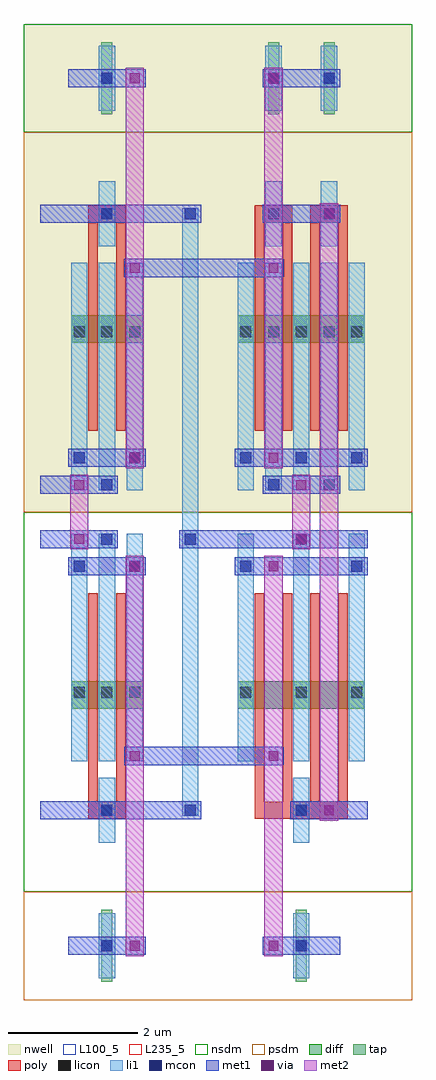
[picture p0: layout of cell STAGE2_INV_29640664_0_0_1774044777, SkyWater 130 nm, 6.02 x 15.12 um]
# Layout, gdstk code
from math import pi, radians
import gdstk
lib = gdstk.Library(unit=1e-6, precision=1e-09)
def R(c, l, rs):  # rectangles x0, y0, x1, y1
    for r in rs: c.add(gdstk.rectangle(r[:2], r[2:], *l))
def A(c, l, x, y, w, h, nx, ny, dx, dy):  # array of equal rectangles
    R(c, l, [(x+i*dx, y+j*dy, x+i*dx+w, y+j*dy+h) for i in range(nx) for j in range(ny)])
def P(c, l, *ps):  # polygons
    for p in ps: c.add(gdstk.Polygon(p, *l))
nwell = (64, 20)
diff = (65, 20)
tap = (65, 44)
poly = (66, 20)
licon = (66, 44)
li1 = (67, 20)
mcon = (67, 44)
met1 = (68, 20)
via = (68, 44)
met2 = (69, 20)
nsdm = (93, 44)
psdm = (94, 20)
L100_5 = (100, 5)
L235_5 = (235, 5)

nmos_s_30545730_x1_y1_17 = lib.new_cell('NMOS_S_30545730_X1_Y1_1774044755_1774044777')
R(nmos_s_30545730_x1_y1_17, diff, [(0.735,2.625,2.705,3.045)])
R(nmos_s_30545730_x1_y1_17, tap, [(1.635,6.16,1.805,7.28)])
A(nmos_s_30545730_x1_y1_17, poly, 1, 1.26, 0.15, 3.36, 4, 1, 0.43, 0)
R(nmos_s_30545730_x1_y1_17, poly, [(1,4.485,2.44,4.755)])
A(nmos_s_30545730_x1_y1_17, licon, 0.775, 2.705, 0.17, 0.17, 3, 1, 0.86, 0)
R(nmos_s_30545730_x1_y1_17, licon, [(1.635,4.535,1.805,4.705), (1.635,6.635,1.805,6.805)])
A(nmos_s_30545730_x1_y1_17, li1, 0.735, 0.335, 0.25, 3.53, 3, 1, 0.86, 0)
R(nmos_s_30545730_x1_y1_17, li1, [(1.595,4.115,1.845,5.125), (1.595,6.215,1.845,7.225)])
R(nmos_s_30545730_x1_y1_17, mcon, [(1.635,0.335,1.805,0.505), (0.775,0.755,0.945,0.925), (2.495,0.755,2.665,0.925), (1.635,4.535,1.805,4.705), (1.635,6.635,1.805,6.805)])
R(nmos_s_30545730_x1_y1_17, met1, [(0.69,0.28,1.89,0.56), (0.69,0.7,2.75,0.98), (0.69,4.48,1.89,4.76), (1.12,6.58,2.32,6.86)])
R(nmos_s_30545730_x1_y1_17, via, [(2.075,0.765,2.225,0.915), (2.075,6.645,2.225,6.795)])
R(nmos_s_30545730_x1_y1_17, met2, [(2.01,0.68,2.29,6.88)])
R(nmos_s_30545730_x1_y1_17, nsdm, [(0,0,3.44,5.88)])
R(nmos_s_30545730_x1_y1_17, psdm, [(0,5.88,3.44,7.56)])
R(nmos_s_30545730_x1_y1_17, L100_5, [(0,0,3.44,7.56)])

nmos_s_96839798_x1_y1_17 = lib.new_cell('NMOS_S_96839798_X1_Y1_1774044756_1774044777')
R(nmos_s_96839798_x1_y1_17, diff, [(0.735,2.625,1.845,3.045)])
R(nmos_s_96839798_x1_y1_17, tap, [(1.205,6.16,1.375,7.28)])
R(nmos_s_96839798_x1_y1_17, poly, [(1,1.26,1.15,4.62), (1.43,1.26,1.58,4.62), (1,4.485,1.58,4.755)])
A(nmos_s_96839798_x1_y1_17, licon, 0.775, 2.705, 0.17, 0.17, 3, 1, 0.43, 0)
R(nmos_s_96839798_x1_y1_17, licon, [(1.205,4.535,1.375,4.705), (1.205,6.635,1.375,6.805)])
A(nmos_s_96839798_x1_y1_17, li1, 0.735, 0.335, 0.25, 3.53, 3, 1, 0.43, 0)
R(nmos_s_96839798_x1_y1_17, li1, [(1.165,4.115,1.415,5.125), (1.165,6.215,1.415,7.225)])
R(nmos_s_96839798_x1_y1_17, mcon, [(1.205,0.335,1.375,0.505), (0.775,0.755,0.945,0.925), (1.635,0.755,1.805,0.925), (1.205,4.535,1.375,4.705), (1.205,6.635,1.375,6.805)])
R(nmos_s_96839798_x1_y1_17, met1, [(0.26,0.28,1.46,0.56), (0.69,0.7,1.89,0.98), (0.26,4.48,1.46,4.76), (0.69,6.58,1.89,6.86)])
R(nmos_s_96839798_x1_y1_17, via, [(1.645,0.765,1.795,0.915), (1.645,6.645,1.795,6.795)])
R(nmos_s_96839798_x1_y1_17, met2, [(1.58,0.68,1.86,6.88)])
R(nmos_s_96839798_x1_y1_17, nsdm, [(0,0,2.58,5.88)])
R(nmos_s_96839798_x1_y1_17, psdm, [(0,5.88,2.58,7.56)])
R(nmos_s_96839798_x1_y1_17, L100_5, [(0,0,2.58,7.56)])

pmos_s_9692504_x2_y1_177 = lib.new_cell('PMOS_S_9692504_X2_Y1_1774044758_1774044777')
R(pmos_s_9692504_x2_y1_177, nwell, [(0,0,3.44,7.56)])
R(pmos_s_9692504_x2_y1_177, diff, [(0.735,2.625,2.705,3.045)])
R(pmos_s_9692504_x2_y1_177, tap, [(1.205,6.16,1.375,7.28), (2.065,6.16,2.235,7.28)])
A(pmos_s_9692504_x2_y1_177, poly, 1, 1.26, 0.15, 3.36, 4, 1, 0.43, 0)
R(pmos_s_9692504_x2_y1_177, poly, [(1,4.485,1.58,4.755), (1.86,4.485,2.44,4.755)])
A(pmos_s_9692504_x2_y1_177, licon, 0.775, 2.705, 0.17, 0.17, 3, 1, 0.43, 0)
A(pmos_s_9692504_x2_y1_177, licon, 1.635, 2.705, 0.17, 0.17, 3, 1, 0.43, 0)
R(pmos_s_9692504_x2_y1_177, licon, [(1.205,4.535,1.375,4.705), (2.065,4.535,2.235,4.705), (1.205,6.635,1.375,6.805), (2.065,6.635,2.235,6.805)])
A(pmos_s_9692504_x2_y1_177, li1, 0.735, 0.335, 0.25, 3.53, 5, 1, 0.43, 0)
R(pmos_s_9692504_x2_y1_177, li1, [(1.165,4.115,1.415,5.125), (2.025,4.115,2.275,5.125), (1.165,6.215,1.415,7.225), (2.025,6.215,2.275,7.225)])
A(pmos_s_9692504_x2_y1_177, mcon, 0.775, 0.755, 0.17, 0.17, 3, 1, 0.86, 0)
R(pmos_s_9692504_x2_y1_177, mcon, [(1.205,0.335,1.375,0.505), (2.065,0.335,2.235,0.505), (1.205,4.535,1.375,4.705), (2.065,4.535,2.235,4.705), (1.205,6.635,1.375,6.805), (2.065,6.635,2.235,6.805)])
R(pmos_s_9692504_x2_y1_177, met1, [(1.12,0.28,2.32,0.56), (0.69,0.7,2.75,0.98), (1.12,4.48,2.32,4.76), (1.12,6.58,2.32,6.86)])
R(pmos_s_9692504_x2_y1_177, via, [(2.075,0.765,2.225,0.915), (2.075,6.645,2.225,6.795)])
R(pmos_s_9692504_x2_y1_177, met2, [(2.01,0.68,2.29,6.88)])
R(pmos_s_9692504_x2_y1_177, nsdm, [(0,5.88,3.44,7.56)])
R(pmos_s_9692504_x2_y1_177, psdm, [(0,0,3.44,5.88)])
R(pmos_s_9692504_x2_y1_177, L100_5, [(0,0,3.44,7.56)])

pmos_s_48783884_x1_y1_17 = lib.new_cell('PMOS_S_48783884_X1_Y1_1774044757_1774044777')
R(pmos_s_48783884_x1_y1_17, nwell, [(0,0,2.58,7.56)])
R(pmos_s_48783884_x1_y1_17, diff, [(0.735,2.625,1.845,3.045)])
R(pmos_s_48783884_x1_y1_17, tap, [(1.205,6.16,1.375,7.28)])
R(pmos_s_48783884_x1_y1_17, poly, [(1,1.26,1.15,4.62), (1.43,1.26,1.58,4.62), (1,4.485,1.58,4.755)])
A(pmos_s_48783884_x1_y1_17, licon, 0.775, 2.705, 0.17, 0.17, 3, 1, 0.43, 0)
R(pmos_s_48783884_x1_y1_17, licon, [(1.205,4.535,1.375,4.705), (1.205,6.635,1.375,6.805)])
A(pmos_s_48783884_x1_y1_17, li1, 0.735, 0.335, 0.25, 3.53, 3, 1, 0.43, 0)
R(pmos_s_48783884_x1_y1_17, li1, [(1.165,4.115,1.415,5.125), (1.165,6.215,1.415,7.225)])
R(pmos_s_48783884_x1_y1_17, mcon, [(1.205,0.335,1.375,0.505), (0.775,0.755,0.945,0.925), (1.635,0.755,1.805,0.925), (1.205,4.535,1.375,4.705), (1.205,6.635,1.375,6.805)])
R(pmos_s_48783884_x1_y1_17, met1, [(0.26,0.28,1.46,0.56), (0.69,0.7,1.89,0.98), (0.26,4.48,1.46,4.76), (0.69,6.58,1.89,6.86)])
R(pmos_s_48783884_x1_y1_17, via, [(1.645,0.765,1.795,0.915), (1.645,6.645,1.795,6.795)])
R(pmos_s_48783884_x1_y1_17, met2, [(1.58,0.68,1.86,6.88)])
R(pmos_s_48783884_x1_y1_17, nsdm, [(0,5.88,2.58,7.56)])
R(pmos_s_48783884_x1_y1_17, psdm, [(0,0,2.58,5.88)])
R(pmos_s_48783884_x1_y1_17, L100_5, [(0,0,2.58,7.56)])

stage2_inv_29640664_0_0_ = lib.new_cell('STAGE2_INV_29640664_0_0_1774044777')
R(stage2_inv_29640664_0_0_, li1, [(2.455,2.855,2.705,3.025), (2.455,2.855,2.705,3.025), (2.455,2.855,2.705,3.025), (2.455,2.855,2.705,3.025), (2.455,2.855,2.705,3.025), (2.455,2.855,2.705,3.025), (2.455,2.94,2.705,7.14), (2.455,7.055,2.705,7.225), (2.455,7.055,2.705,7.225), (2.455,7.055,2.705,7.225), (2.455,7.055,2.705,7.225), (2.455,7.055,2.705,7.225), (2.455,7.055,2.705,7.225), (2.455,7.14,2.705,12.18), (2.455,12.095,2.705,12.265), (2.455,12.095,2.705,12.265)])
R(stage2_inv_29640664_0_0_, mcon, [(2.495,2.855,2.665,3.025), (2.495,2.855,2.665,3.025), (2.495,2.855,2.665,3.025), (2.495,2.855,2.665,3.025), (2.495,2.855,2.665,3.025), (2.495,2.855,2.665,3.025), (2.495,7.055,2.665,7.225), (2.495,7.055,2.665,7.225), (2.495,7.055,2.665,7.225), (2.495,7.055,2.665,7.225), (2.495,7.055,2.665,7.225), (2.495,7.055,2.665,7.225), (2.495,12.095,2.665,12.265), (2.495,12.095,2.665,12.265)])
R(stage2_inv_29640664_0_0_, met1, [(1.29,2.8,2.58,3.08), (2.41,2.8,2.75,3.08), (2.41,2.8,2.75,3.08), (2.41,2.8,2.75,3.08), (2.41,2.8,2.75,3.08), (2.41,2.8,2.75,3.08), (2.41,2.8,2.75,3.08), (4.57,2.8,4.89,3.08), (4.57,2.8,4.89,3.08), (1.56,3.64,1.88,3.92), (1.56,3.64,1.88,3.92), (1.72,3.64,3.87,3.92), (3.71,3.64,4.03,3.92), (3.71,3.64,4.03,3.92), (0.7,7,1.02,7.28), (0.7,7,1.02,7.28), (2.41,7,2.75,7.28), (2.41,7,2.75,7.28), (2.41,7,2.75,7.28), (2.41,7,2.75,7.28), (2.41,7,2.75,7.28), (2.41,7,2.75,7.28), (2.58,7,4.3,7.28), (4.14,7,4.46,7.28), (4.14,7,4.46,7.28), (4.14,7,4.46,7.28), (4.14,7,4.46,7.28), (0.7,7.84,1.02,8.12), (0.7,7.84,1.02,8.12), (4.14,7.84,4.46,8.12), (4.14,7.84,4.46,8.12), (4.14,7.84,4.46,8.12), (4.14,7.84,4.46,8.12), (1.56,11.2,1.88,11.48), (1.56,11.2,1.88,11.48), (1.72,11.2,3.87,11.48), (3.71,11.2,4.03,11.48), (3.71,11.2,4.03,11.48), (1.29,12.04,2.58,12.32), (2.41,12.04,2.75,12.32), (2.41,12.04,2.75,12.32), (4.57,12.04,4.89,12.32), (4.57,12.04,4.89,12.32)])
P(stage2_inv_29640664_0_0_, met1, [(0,0),(0,0),(0,0),(0,0)],
  [(0,0),(0,0),(0,0),(0,0)],
  [(0,0),(0,0),(0,0),(0,0)],
  [(0,0),(0,0),(0,0),(0,0)],
  [(0,0),(0,0),(0,0),(0,0)],
  [(0,0),(0,0),(0,0),(0,0)],
  [(0,0),(0,0),(0,0),(0,0)],
  [(0,0),(0,0),(0,0),(0,0)])
R(stage2_inv_29640664_0_0_, via, [(4.655,2.865,4.805,3.015), (4.655,2.865,4.805,3.015), (1.645,3.705,1.795,3.855), (1.645,3.705,1.795,3.855), (3.795,3.705,3.945,3.855), (3.795,3.705,3.945,3.855), (0.785,7.065,0.935,7.215), (0.785,7.065,0.935,7.215), (4.225,7.065,4.375,7.215), (4.225,7.065,4.375,7.215), (4.225,7.065,4.375,7.215), (4.225,7.065,4.375,7.215), (0.785,7.905,0.935,8.055), (0.785,7.905,0.935,8.055), (4.225,7.905,4.375,8.055), (4.225,7.905,4.375,8.055), (4.225,7.905,4.375,8.055), (4.225,7.905,4.375,8.055), (1.645,11.265,1.795,11.415), (1.645,11.265,1.795,11.415), (3.795,11.265,3.945,11.415), (3.795,11.265,3.945,11.415), (4.655,12.105,4.805,12.255), (4.655,12.105,4.805,12.255)])
R(stage2_inv_29640664_0_0_, met2, [(4.59,2.78,4.87,3.1), (4.59,2.78,4.87,3.1), (4.59,2.94,4.87,12.18), (1.58,3.62,1.86,3.94), (1.58,3.62,1.86,3.94), (3.73,3.62,4.01,3.94), (3.73,3.62,4.01,3.94), (0.72,6.98,1,7.3), (0.72,6.98,1,7.3), (4.16,6.98,4.44,7.3), (4.16,6.98,4.44,7.3), (4.16,6.98,4.44,7.3), (4.16,6.98,4.44,7.3), (0.72,7.14,1,7.98), (4.16,7.14,4.44,7.98), (0.72,7.82,1,8.14), (0.72,7.82,1,8.14), (4.16,7.82,4.44,8.14), (4.16,7.82,4.44,8.14), (4.16,7.82,4.44,8.14), (4.16,7.82,4.44,8.14), (1.58,11.18,1.86,11.5), (1.58,11.18,1.86,11.5), (3.73,11.18,4.01,11.5), (3.73,11.18,4.01,11.5), (4.59,12.02,4.87,12.34), (4.59,12.02,4.87,12.34)])
P(stage2_inv_29640664_0_0_, met2, [(0,0),(0,0),(0,0),(0,0)],
  [(0,0),(0,0),(0,0),(0,0)],
  [(0,0),(0,0),(0,0),(0,0)],
  [(0,0),(0,0),(0,0),(0,0)])
R(stage2_inv_29640664_0_0_, L235_5, [(0,0,6.02,15.12)])
stage2_inv_29640664_0_0_.add(gdstk.Reference(nmos_s_30545730_x1_y1_17, (6.02,7.56), rotation=pi))
stage2_inv_29640664_0_0_.add(gdstk.Reference(nmos_s_96839798_x1_y1_17, (0,7.56), x_reflection=True))
stage2_inv_29640664_0_0_.add(gdstk.Reference(pmos_s_9692504_x2_y1_177, (6.02,7.56), rotation=pi, x_reflection=True))
stage2_inv_29640664_0_0_.add(gdstk.Reference(pmos_s_48783884_x1_y1_17, (0,7.56)))

lib.write_gds('STAGE2_INV_29640664_0_0_1774044777.gds')
